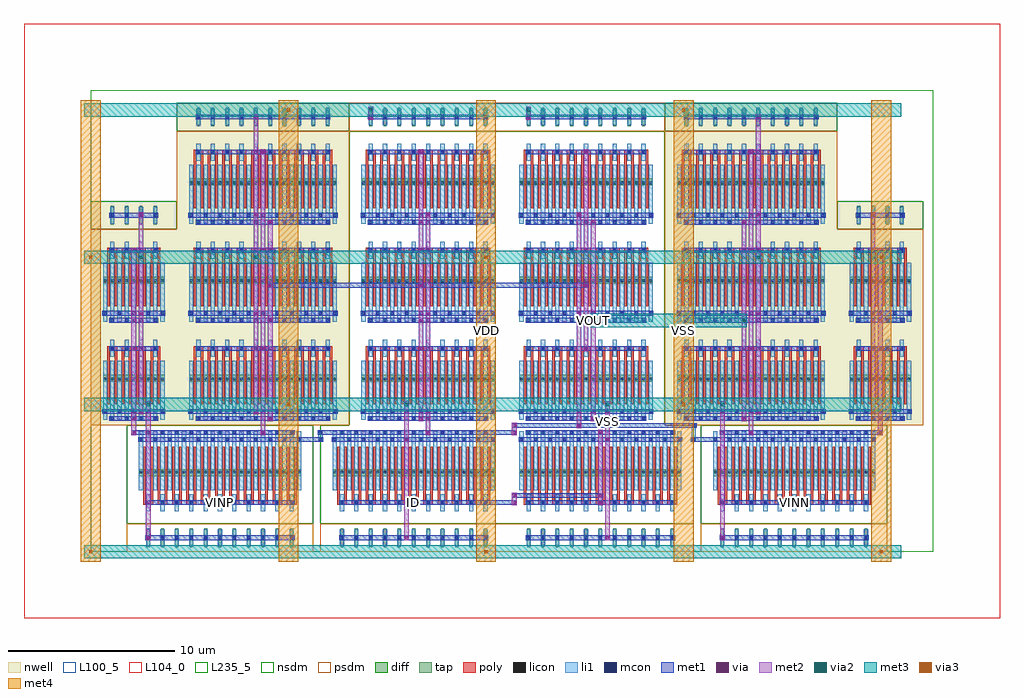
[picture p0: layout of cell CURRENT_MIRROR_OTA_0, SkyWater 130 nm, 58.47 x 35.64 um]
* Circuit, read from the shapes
.subckt CURRENT_MIRROR_OTA_0 ID VDD VINN VINP VOUT VSS
XM1 n1 VINP n2 VSS sky130_fd_pr__nfet_01v8 w=0.42 l=0.15 m=22
XM2 n2 ID VSS VSS sky130_fd_pr__nfet_01v8 w=0.42 l=0.15 m=22
XM3 n3 n3 n2 VSS sky130_fd_pr__nfet_01v8 w=0.42 l=0.15 m=54
XM4 ID ID VSS VSS sky130_fd_pr__nfet_01v8 w=0.42 l=0.15 m=22
XM5 VOUT n3 n2 VSS sky130_fd_pr__nfet_01v8 w=0.42 l=0.15 m=54
XM6 n4 VINN n2 VSS sky130_fd_pr__nfet_01v8 w=0.42 l=0.15 m=22
XM7 n1 n1 VDD VDD sky130_fd_pr__pfet_01v8 w=0.42 l=0.15 m=16
XM8 n3 n1 VDD VDD sky130_fd_pr__pfet_01v8 w=0.42 l=0.15 m=60
XM9 VOUT n4 VDD VDD sky130_fd_pr__pfet_01v8 w=0.42 l=0.15 m=60
XM10 n4 n4 VDD VDD sky130_fd_pr__pfet_01v8 w=0.42 l=0.15 m=16
.ends

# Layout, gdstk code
from math import pi, radians
import gdstk
lib = gdstk.Library(unit=1e-6, precision=1e-09)
def R(c, l, rs):  # rectangles x0, y0, x1, y1
    for r in rs: c.add(gdstk.rectangle(r[:2], r[2:], *l))
def A(c, l, x, y, w, h, nx, ny, dx, dy):  # array of equal rectangles
    R(c, l, [(x+i*dx, y+j*dy, x+i*dx+w, y+j*dy+h) for i in range(nx) for j in range(ny)])
def P(c, l, *ps):  # polygons
    for p in ps: c.add(gdstk.Polygon(p, *l))
nwell = (64, 20)
diff = (65, 20)
tap = (65, 44)
poly = (66, 20)
licon = (66, 44)
li1 = (67, 20)
mcon = (67, 44)
met1 = (68, 20)
via = (68, 44)
met2 = (69, 20)
via2 = (69, 44)
met3 = (70, 20)
via3 = (70, 44)
met4 = (71, 20)
nsdm = (93, 44)
psdm = (94, 20)
L100_5 = (100, 5)
L104_0 = (104, 0)
L235_5 = (235, 5)

dcl_nmos_s_92344100_x11_ = lib.new_cell('DCL_NMOS_S_92344100_X11_Y1_1725293918')
R(dcl_nmos_s_92344100_x11_, diff, [(0.735,2.625,10.445,3.045)])
A(dcl_nmos_s_92344100_x11_, tap, 1.205, 6.16, 0.17, 1.12, 11, 1, 0.86, 0)
A(dcl_nmos_s_92344100_x11_, poly, 1, 1.26, 0.15, 3.36, 22, 1, 0.43, 0)
A(dcl_nmos_s_92344100_x11_, poly, 1, 4.485, 0.58, 0.27, 11, 1, 0.86, 0)
A(dcl_nmos_s_92344100_x11_, licon, 0.775, 2.705, 0.17, 0.17, 3, 1, 0.43, 0)
A(dcl_nmos_s_92344100_x11_, licon, 1.635, 2.705, 0.17, 0.17, 3, 1, 0.43, 0)
A(dcl_nmos_s_92344100_x11_, licon, 2.495, 2.705, 0.17, 0.17, 3, 1, 0.43, 0)
A(dcl_nmos_s_92344100_x11_, licon, 3.355, 2.705, 0.17, 0.17, 3, 1, 0.43, 0)
A(dcl_nmos_s_92344100_x11_, licon, 4.215, 2.705, 0.17, 0.17, 3, 1, 0.43, 0)
A(dcl_nmos_s_92344100_x11_, licon, 5.075, 2.705, 0.17, 0.17, 3, 1, 0.43, 0)
A(dcl_nmos_s_92344100_x11_, licon, 5.935, 2.705, 0.17, 0.17, 3, 1, 0.43, 0)
A(dcl_nmos_s_92344100_x11_, licon, 6.795, 2.705, 0.17, 0.17, 3, 1, 0.43, 0)
A(dcl_nmos_s_92344100_x11_, licon, 7.655, 2.705, 0.17, 0.17, 3, 1, 0.43, 0)
A(dcl_nmos_s_92344100_x11_, licon, 8.515, 2.705, 0.17, 0.17, 3, 1, 0.43, 0)
A(dcl_nmos_s_92344100_x11_, licon, 9.375, 2.705, 0.17, 0.17, 3, 1, 0.43, 0)
A(dcl_nmos_s_92344100_x11_, licon, 1.205, 4.535, 0.17, 0.17, 11, 2, 0.86, 2.1)
A(dcl_nmos_s_92344100_x11_, li1, 0.735, 0.335, 0.25, 3.53, 23, 1, 0.43, 0)
A(dcl_nmos_s_92344100_x11_, li1, 1.165, 4.115, 0.25, 1.01, 11, 2, 0.86, 2.1)
A(dcl_nmos_s_92344100_x11_, mcon, 1.205, 0.335, 0.17, 0.17, 11, 2, 0.86, 4.2)
A(dcl_nmos_s_92344100_x11_, mcon, 0.775, 0.755, 0.17, 0.17, 12, 1, 0.86, 0)
A(dcl_nmos_s_92344100_x11_, mcon, 1.205, 6.635, 0.17, 0.17, 11, 1, 0.86, 0)
R(dcl_nmos_s_92344100_x11_, met1, [(1.12,0.28,10.06,0.56), (0.69,0.7,10.49,0.98), (1.12,4.48,10.06,4.76), (1.12,6.58,10.06,6.86)])
R(dcl_nmos_s_92344100_x11_, via, [(5.515,0.345,5.665,0.495), (5.945,0.765,6.095,0.915), (5.515,4.545,5.665,4.695), (5.945,6.645,6.095,6.795)])
R(dcl_nmos_s_92344100_x11_, met2, [(5.45,0.26,5.73,4.78), (5.88,0.68,6.16,6.88)])
R(dcl_nmos_s_92344100_x11_, nsdm, [(0,0,11.18,5.88)])
R(dcl_nmos_s_92344100_x11_, psdm, [(0,5.88,11.18,7.56)])
R(dcl_nmos_s_92344100_x11_, L100_5, [(0,0,11.18,7.56)])

dcl_pmos_s_60690635_x4_y = lib.new_cell('DCL_PMOS_S_60690635_X4_Y2_1725293919')
R(dcl_pmos_s_60690635_x4_y, nwell, [(0,0,5.16,13.44)])
R(dcl_pmos_s_60690635_x4_y, diff, [(0.735,2.625,4.425,3.045), (0.735,8.505,4.425,8.925)])
A(dcl_pmos_s_60690635_x4_y, tap, 1.205, 12.04, 0.17, 1.12, 4, 1, 0.86, 0)
A(dcl_pmos_s_60690635_x4_y, poly, 1, 1.26, 0.15, 3.36, 8, 2, 0.43, 5.88)
A(dcl_pmos_s_60690635_x4_y, poly, 1, 4.485, 0.58, 0.27, 4, 2, 0.86, 5.88)
A(dcl_pmos_s_60690635_x4_y, licon, 0.775, 2.705, 0.17, 0.17, 3, 2, 0.43, 5.88)
A(dcl_pmos_s_60690635_x4_y, licon, 1.635, 2.705, 0.17, 0.17, 3, 2, 0.43, 5.88)
A(dcl_pmos_s_60690635_x4_y, licon, 2.495, 2.705, 0.17, 0.17, 3, 2, 0.43, 5.88)
A(dcl_pmos_s_60690635_x4_y, licon, 3.355, 2.705, 0.17, 0.17, 3, 2, 0.43, 5.88)
A(dcl_pmos_s_60690635_x4_y, licon, 1.205, 4.535, 0.17, 0.17, 4, 2, 0.86, 5.88)
R(dcl_pmos_s_60690635_x4_y, licon, [(1.205,12.515,1.375,12.685), (1.205,12.515,1.375,12.685), (2.065,12.515,2.235,12.685), (2.065,12.515,2.235,12.685), (2.925,12.515,3.095,12.685), (2.925,12.515,3.095,12.685), (3.785,12.515,3.955,12.685), (3.785,12.515,3.955,12.685)])
A(dcl_pmos_s_60690635_x4_y, li1, 0.735, 0.335, 0.25, 3.53, 9, 2, 0.43, 5.88)
A(dcl_pmos_s_60690635_x4_y, li1, 1.165, 4.115, 0.25, 1.01, 4, 2, 0.86, 5.88)
A(dcl_pmos_s_60690635_x4_y, li1, 1.165, 12.095, 0.25, 1.01, 4, 1, 0.86, 0)
A(dcl_pmos_s_60690635_x4_y, mcon, 1.205, 0.335, 0.17, 0.17, 4, 2, 0.86, 4.2)
A(dcl_pmos_s_60690635_x4_y, mcon, 0.775, 0.755, 0.17, 0.17, 5, 2, 0.86, 5.88)
A(dcl_pmos_s_60690635_x4_y, mcon, 1.205, 6.215, 0.17, 0.17, 4, 2, 0.86, 4.2)
A(dcl_pmos_s_60690635_x4_y, mcon, 1.205, 12.515, 0.17, 0.17, 4, 1, 0.86, 0)
R(dcl_pmos_s_60690635_x4_y, met1, [(1.12,0.28,4.04,0.56), (0.69,0.7,4.47,0.98), (1.12,4.48,4.04,4.76), (1.12,6.16,4.04,6.44), (0.69,6.58,4.47,6.86), (1.12,10.36,4.04,10.64), (1.12,12.46,4.04,12.74)])
A(dcl_pmos_s_60690635_x4_y, via, 2.935, 0.765, 0.15, 0.15, 1, 3, 0, 5.88)
R(dcl_pmos_s_60690635_x4_y, via, [(2.505,0.345,2.655,0.495), (2.505,4.545,2.655,4.695), (2.505,6.225,2.655,6.375), (2.505,10.425,2.655,10.575)])
R(dcl_pmos_s_60690635_x4_y, met2, [(2.44,0.26,2.72,10.66), (2.87,0.68,3.15,12.76)])
R(dcl_pmos_s_60690635_x4_y, nsdm, [(0,11.76,5.16,13.44)])
R(dcl_pmos_s_60690635_x4_y, psdm, [(0,0,5.16,11.76)])
R(dcl_pmos_s_60690635_x4_y, L100_5, [(0,0,5.16,13.44)])

nmos_s_41291443_x11_y1_1 = lib.new_cell('NMOS_S_41291443_X11_Y1_1725293922')
R(nmos_s_41291443_x11_y1_1, diff, [(0.735,2.625,10.445,3.045)])
A(nmos_s_41291443_x11_y1_1, tap, 1.205, 6.16, 0.17, 1.12, 11, 1, 0.86, 0)
A(nmos_s_41291443_x11_y1_1, poly, 1, 1.26, 0.15, 3.36, 22, 1, 0.43, 0)
A(nmos_s_41291443_x11_y1_1, poly, 1, 4.485, 0.58, 0.27, 11, 1, 0.86, 0)
A(nmos_s_41291443_x11_y1_1, licon, 0.775, 2.705, 0.17, 0.17, 3, 1, 0.43, 0)
A(nmos_s_41291443_x11_y1_1, licon, 1.635, 2.705, 0.17, 0.17, 3, 1, 0.43, 0)
A(nmos_s_41291443_x11_y1_1, licon, 2.495, 2.705, 0.17, 0.17, 3, 1, 0.43, 0)
A(nmos_s_41291443_x11_y1_1, licon, 3.355, 2.705, 0.17, 0.17, 3, 1, 0.43, 0)
A(nmos_s_41291443_x11_y1_1, licon, 4.215, 2.705, 0.17, 0.17, 3, 1, 0.43, 0)
A(nmos_s_41291443_x11_y1_1, licon, 5.075, 2.705, 0.17, 0.17, 3, 1, 0.43, 0)
A(nmos_s_41291443_x11_y1_1, licon, 5.935, 2.705, 0.17, 0.17, 3, 1, 0.43, 0)
A(nmos_s_41291443_x11_y1_1, licon, 6.795, 2.705, 0.17, 0.17, 3, 1, 0.43, 0)
A(nmos_s_41291443_x11_y1_1, licon, 7.655, 2.705, 0.17, 0.17, 3, 1, 0.43, 0)
A(nmos_s_41291443_x11_y1_1, licon, 8.515, 2.705, 0.17, 0.17, 3, 1, 0.43, 0)
A(nmos_s_41291443_x11_y1_1, licon, 9.375, 2.705, 0.17, 0.17, 3, 1, 0.43, 0)
A(nmos_s_41291443_x11_y1_1, licon, 1.205, 4.535, 0.17, 0.17, 11, 2, 0.86, 2.1)
A(nmos_s_41291443_x11_y1_1, li1, 0.735, 0.335, 0.25, 3.53, 23, 1, 0.43, 0)
A(nmos_s_41291443_x11_y1_1, li1, 1.165, 4.115, 0.25, 1.01, 11, 2, 0.86, 2.1)
A(nmos_s_41291443_x11_y1_1, mcon, 1.205, 0.335, 0.17, 0.17, 11, 2, 0.86, 4.2)
A(nmos_s_41291443_x11_y1_1, mcon, 0.775, 0.755, 0.17, 0.17, 12, 1, 0.86, 0)
A(nmos_s_41291443_x11_y1_1, mcon, 1.205, 6.635, 0.17, 0.17, 11, 1, 0.86, 0)
R(nmos_s_41291443_x11_y1_1, met1, [(1.12,0.28,10.06,0.56), (0.69,0.7,10.49,0.98), (1.12,4.48,10.06,4.76), (1.12,6.58,10.06,6.86)])
R(nmos_s_41291443_x11_y1_1, via, [(5.945,0.765,6.095,0.915), (5.945,6.645,6.095,6.795)])
R(nmos_s_41291443_x11_y1_1, met2, [(5.88,0.68,6.16,6.88)])
R(nmos_s_41291443_x11_y1_1, nsdm, [(0,0,11.18,5.88)])
R(nmos_s_41291443_x11_y1_1, psdm, [(0,5.88,11.18,7.56)])
R(nmos_s_41291443_x11_y1_1, L100_5, [(0,0,11.18,7.56)])

pmos_s_33763385_x10_y3_1 = lib.new_cell('PMOS_S_33763385_X10_Y3_1725293923')
R(pmos_s_33763385_x10_y3_1, nwell, [(0,0,10.32,19.32)])
A(pmos_s_33763385_x10_y3_1, diff, 0.735, 2.625, 8.85, 0.42, 1, 3, 0, 5.88)
A(pmos_s_33763385_x10_y3_1, tap, 1.205, 17.92, 0.17, 1.12, 10, 1, 0.86, 0)
A(pmos_s_33763385_x10_y3_1, poly, 1, 1.26, 0.15, 3.36, 20, 3, 0.43, 5.88)
A(pmos_s_33763385_x10_y3_1, poly, 1, 4.485, 0.58, 0.27, 10, 3, 0.86, 5.88)
A(pmos_s_33763385_x10_y3_1, licon, 0.775, 2.705, 0.17, 0.17, 3, 3, 0.43, 5.88)
A(pmos_s_33763385_x10_y3_1, licon, 1.635, 2.705, 0.17, 0.17, 3, 3, 0.43, 5.88)
A(pmos_s_33763385_x10_y3_1, licon, 2.495, 2.705, 0.17, 0.17, 3, 3, 0.43, 5.88)
A(pmos_s_33763385_x10_y3_1, licon, 3.355, 2.705, 0.17, 0.17, 3, 3, 0.43, 5.88)
A(pmos_s_33763385_x10_y3_1, licon, 4.215, 2.705, 0.17, 0.17, 3, 3, 0.43, 5.88)
A(pmos_s_33763385_x10_y3_1, licon, 5.075, 2.705, 0.17, 0.17, 3, 3, 0.43, 5.88)
A(pmos_s_33763385_x10_y3_1, licon, 5.935, 2.705, 0.17, 0.17, 3, 3, 0.43, 5.88)
A(pmos_s_33763385_x10_y3_1, licon, 6.795, 2.705, 0.17, 0.17, 3, 3, 0.43, 5.88)
A(pmos_s_33763385_x10_y3_1, licon, 7.655, 2.705, 0.17, 0.17, 3, 3, 0.43, 5.88)
A(pmos_s_33763385_x10_y3_1, licon, 8.515, 2.705, 0.17, 0.17, 3, 3, 0.43, 5.88)
A(pmos_s_33763385_x10_y3_1, licon, 1.205, 4.535, 0.17, 0.17, 10, 3, 0.86, 5.88)
R(pmos_s_33763385_x10_y3_1, licon, [(1.205,18.395,1.375,18.565), (1.205,18.395,1.375,18.565), (1.205,18.395,1.375,18.565), (2.065,18.395,2.235,18.565), (2.065,18.395,2.235,18.565), (2.065,18.395,2.235,18.565), (2.925,18.395,3.095,18.565), (2.925,18.395,3.095,18.565), (2.925,18.395,3.095,18.565), (3.785,18.395,3.955,18.565), (3.785,18.395,3.955,18.565), (3.785,18.395,3.955,18.565), (4.645,18.395,4.815,18.565), (4.645,18.395,4.815,18.565), (4.645,18.395,4.815,18.565), (5.505,18.395,5.675,18.565), (5.505,18.395,5.675,18.565), (5.505,18.395,5.675,18.565), (6.365,18.395,6.535,18.565), (6.365,18.395,6.535,18.565), (6.365,18.395,6.535,18.565), (7.225,18.395,7.395,18.565), (7.225,18.395,7.395,18.565), (7.225,18.395,7.395,18.565), (8.085,18.395,8.255,18.565), (8.085,18.395,8.255,18.565), (8.085,18.395,8.255,18.565), (8.945,18.395,9.115,18.565), (8.945,18.395,9.115,18.565), (8.945,18.395,9.115,18.565)])
A(pmos_s_33763385_x10_y3_1, li1, 0.735, 0.335, 0.25, 3.53, 21, 3, 0.43, 5.88)
A(pmos_s_33763385_x10_y3_1, li1, 1.165, 4.115, 0.25, 1.01, 10, 3, 0.86, 5.88)
A(pmos_s_33763385_x10_y3_1, li1, 1.165, 17.975, 0.25, 1.01, 10, 1, 0.86, 0)
A(pmos_s_33763385_x10_y3_1, mcon, 1.205, 0.335, 0.17, 0.17, 10, 2, 0.86, 4.2)
A(pmos_s_33763385_x10_y3_1, mcon, 0.775, 0.755, 0.17, 0.17, 11, 3, 0.86, 5.88)
A(pmos_s_33763385_x10_y3_1, mcon, 1.205, 6.215, 0.17, 0.17, 10, 2, 0.86, 4.2)
A(pmos_s_33763385_x10_y3_1, mcon, 1.205, 12.095, 0.17, 0.17, 10, 2, 0.86, 4.2)
A(pmos_s_33763385_x10_y3_1, mcon, 1.205, 18.395, 0.17, 0.17, 10, 1, 0.86, 0)
A(pmos_s_33763385_x10_y3_1, met1, 0.69, 0.7, 8.94, 0.28, 1, 3, 0, 5.88)
R(pmos_s_33763385_x10_y3_1, met1, [(1.12,0.28,9.2,0.56), (1.12,4.48,9.2,4.76), (1.12,6.16,9.2,6.44), (1.12,10.36,9.2,10.64), (1.12,12.04,9.2,12.32), (1.12,16.24,9.2,16.52), (1.12,18.34,9.2,18.62)])
A(pmos_s_33763385_x10_y3_1, via, 4.655, 0.345, 0.15, 0.15, 1, 3, 0, 5.88)
A(pmos_s_33763385_x10_y3_1, via, 5.515, 0.765, 0.15, 0.15, 1, 4, 0, 5.88)
A(pmos_s_33763385_x10_y3_1, via, 5.085, 4.545, 0.15, 0.15, 1, 3, 0, 5.88)
R(pmos_s_33763385_x10_y3_1, met2, [(4.59,0.26,4.87,12.34), (5.45,0.68,5.73,18.64), (5.02,4.46,5.3,16.54)])
R(pmos_s_33763385_x10_y3_1, nsdm, [(0,17.64,10.32,19.32)])
R(pmos_s_33763385_x10_y3_1, psdm, [(0,0,10.32,17.64)])
R(pmos_s_33763385_x10_y3_1, L100_5, [(0,0,10.32,19.32)])

dcl_nmos_22653440_x9_y3_ = lib.new_cell('DCL_NMOS_22653440_X9_Y3_1725293917')
A(dcl_nmos_22653440_x9_y3_, diff, 0.735, 2.625, 7.99, 0.42, 1, 3, 0, 5.88)
A(dcl_nmos_22653440_x9_y3_, tap, 1.205, 17.92, 0.17, 1.12, 9, 1, 0.86, 0)
A(dcl_nmos_22653440_x9_y3_, poly, 1, 1.26, 0.15, 3.36, 18, 3, 0.43, 5.88)
A(dcl_nmos_22653440_x9_y3_, poly, 1, 4.485, 0.58, 0.27, 9, 3, 0.86, 5.88)
A(dcl_nmos_22653440_x9_y3_, licon, 0.775, 2.705, 0.17, 0.17, 3, 3, 0.43, 5.88)
A(dcl_nmos_22653440_x9_y3_, licon, 1.635, 2.705, 0.17, 0.17, 3, 3, 0.43, 5.88)
A(dcl_nmos_22653440_x9_y3_, licon, 2.495, 2.705, 0.17, 0.17, 3, 3, 0.43, 5.88)
A(dcl_nmos_22653440_x9_y3_, licon, 3.355, 2.705, 0.17, 0.17, 3, 3, 0.43, 5.88)
A(dcl_nmos_22653440_x9_y3_, licon, 4.215, 2.705, 0.17, 0.17, 3, 3, 0.43, 5.88)
A(dcl_nmos_22653440_x9_y3_, licon, 5.075, 2.705, 0.17, 0.17, 3, 3, 0.43, 5.88)
A(dcl_nmos_22653440_x9_y3_, licon, 5.935, 2.705, 0.17, 0.17, 3, 3, 0.43, 5.88)
A(dcl_nmos_22653440_x9_y3_, licon, 6.795, 2.705, 0.17, 0.17, 3, 3, 0.43, 5.88)
A(dcl_nmos_22653440_x9_y3_, licon, 7.655, 2.705, 0.17, 0.17, 3, 3, 0.43, 5.88)
A(dcl_nmos_22653440_x9_y3_, licon, 1.205, 4.535, 0.17, 0.17, 9, 3, 0.86, 5.88)
R(dcl_nmos_22653440_x9_y3_, licon, [(1.205,18.395,1.375,18.565), (1.205,18.395,1.375,18.565), (1.205,18.395,1.375,18.565), (2.065,18.395,2.235,18.565), (2.065,18.395,2.235,18.565), (2.065,18.395,2.235,18.565), (2.925,18.395,3.095,18.565), (2.925,18.395,3.095,18.565), (2.925,18.395,3.095,18.565), (3.785,18.395,3.955,18.565), (3.785,18.395,3.955,18.565), (3.785,18.395,3.955,18.565), (4.645,18.395,4.815,18.565), (4.645,18.395,4.815,18.565), (4.645,18.395,4.815,18.565), (5.505,18.395,5.675,18.565), (5.505,18.395,5.675,18.565), (5.505,18.395,5.675,18.565), (6.365,18.395,6.535,18.565), (6.365,18.395,6.535,18.565), (6.365,18.395,6.535,18.565), (7.225,18.395,7.395,18.565), (7.225,18.395,7.395,18.565), (7.225,18.395,7.395,18.565), (8.085,18.395,8.255,18.565), (8.085,18.395,8.255,18.565), (8.085,18.395,8.255,18.565)])
A(dcl_nmos_22653440_x9_y3_, li1, 0.735, 0.335, 0.25, 3.53, 19, 3, 0.43, 5.88)
A(dcl_nmos_22653440_x9_y3_, li1, 1.165, 4.115, 0.25, 1.01, 9, 3, 0.86, 5.88)
A(dcl_nmos_22653440_x9_y3_, li1, 1.165, 17.975, 0.25, 1.01, 9, 1, 0.86, 0)
A(dcl_nmos_22653440_x9_y3_, mcon, 1.205, 0.335, 0.17, 0.17, 9, 2, 0.86, 4.2)
A(dcl_nmos_22653440_x9_y3_, mcon, 0.775, 0.755, 0.17, 0.17, 10, 3, 0.86, 5.88)
A(dcl_nmos_22653440_x9_y3_, mcon, 1.205, 6.215, 0.17, 0.17, 9, 2, 0.86, 4.2)
A(dcl_nmos_22653440_x9_y3_, mcon, 1.205, 12.095, 0.17, 0.17, 9, 2, 0.86, 4.2)
A(dcl_nmos_22653440_x9_y3_, mcon, 1.205, 18.395, 0.17, 0.17, 9, 1, 0.86, 0)
A(dcl_nmos_22653440_x9_y3_, met1, 0.69, 0.7, 8.08, 0.28, 1, 3, 0, 5.88)
R(dcl_nmos_22653440_x9_y3_, met1, [(1.12,0.28,8.34,0.56), (1.12,4.48,8.34,4.76), (1.12,6.16,8.34,6.44), (1.12,10.36,8.34,10.64), (1.12,12.04,8.34,12.32), (1.12,16.24,8.34,16.52), (1.12,18.34,8.34,18.62)])
A(dcl_nmos_22653440_x9_y3_, via, 4.655, 0.765, 0.15, 0.15, 1, 3, 0, 5.88)
R(dcl_nmos_22653440_x9_y3_, via, [(4.225,0.345,4.375,0.495), (4.225,4.545,4.375,4.695), (4.225,6.225,4.375,6.375), (4.225,10.425,4.375,10.575), (4.225,12.105,4.375,12.255), (4.225,16.305,4.375,16.455)])
R(dcl_nmos_22653440_x9_y3_, met2, [(4.16,0.26,4.44,16.54), (4.59,0.68,4.87,12.76)])
R(dcl_nmos_22653440_x9_y3_, nsdm, [(0,0,9.46,17.64)])
R(dcl_nmos_22653440_x9_y3_, psdm, [(0,17.64,9.46,19.32)])
R(dcl_nmos_22653440_x9_y3_, L100_5, [(0,0,9.46,19.32)])

nmos_4t_75303516_x11_y1_ = lib.new_cell('NMOS_4T_75303516_X11_Y1_1725293921')
R(nmos_4t_75303516_x11_y1_, diff, [(0.735,2.625,10.445,3.045)])
A(nmos_4t_75303516_x11_y1_, tap, 1.205, 6.16, 0.17, 1.12, 11, 1, 0.86, 0)
A(nmos_4t_75303516_x11_y1_, poly, 1, 1.26, 0.15, 3.36, 22, 1, 0.43, 0)
A(nmos_4t_75303516_x11_y1_, poly, 1, 4.485, 0.58, 0.27, 11, 1, 0.86, 0)
A(nmos_4t_75303516_x11_y1_, licon, 0.775, 2.705, 0.17, 0.17, 3, 1, 0.43, 0)
A(nmos_4t_75303516_x11_y1_, licon, 1.635, 2.705, 0.17, 0.17, 3, 1, 0.43, 0)
A(nmos_4t_75303516_x11_y1_, licon, 2.495, 2.705, 0.17, 0.17, 3, 1, 0.43, 0)
A(nmos_4t_75303516_x11_y1_, licon, 3.355, 2.705, 0.17, 0.17, 3, 1, 0.43, 0)
A(nmos_4t_75303516_x11_y1_, licon, 4.215, 2.705, 0.17, 0.17, 3, 1, 0.43, 0)
A(nmos_4t_75303516_x11_y1_, licon, 5.075, 2.705, 0.17, 0.17, 3, 1, 0.43, 0)
A(nmos_4t_75303516_x11_y1_, licon, 5.935, 2.705, 0.17, 0.17, 3, 1, 0.43, 0)
A(nmos_4t_75303516_x11_y1_, licon, 6.795, 2.705, 0.17, 0.17, 3, 1, 0.43, 0)
A(nmos_4t_75303516_x11_y1_, licon, 7.655, 2.705, 0.17, 0.17, 3, 1, 0.43, 0)
A(nmos_4t_75303516_x11_y1_, licon, 8.515, 2.705, 0.17, 0.17, 3, 1, 0.43, 0)
A(nmos_4t_75303516_x11_y1_, licon, 9.375, 2.705, 0.17, 0.17, 3, 1, 0.43, 0)
A(nmos_4t_75303516_x11_y1_, licon, 1.205, 4.535, 0.17, 0.17, 11, 2, 0.86, 2.1)
A(nmos_4t_75303516_x11_y1_, li1, 0.735, 0.335, 0.25, 3.53, 23, 1, 0.43, 0)
A(nmos_4t_75303516_x11_y1_, li1, 1.165, 4.115, 0.25, 1.01, 11, 2, 0.86, 2.1)
A(nmos_4t_75303516_x11_y1_, mcon, 1.205, 0.335, 0.17, 0.17, 11, 2, 0.86, 4.2)
A(nmos_4t_75303516_x11_y1_, mcon, 0.775, 0.755, 0.17, 0.17, 12, 1, 0.86, 0)
A(nmos_4t_75303516_x11_y1_, mcon, 1.205, 6.635, 0.17, 0.17, 11, 1, 0.86, 0)
R(nmos_4t_75303516_x11_y1_, met1, [(1.12,0.28,10.06,0.56), (0.69,0.7,10.49,0.98), (1.12,4.48,10.06,4.76), (1.12,6.58,10.06,6.86)])
R(nmos_4t_75303516_x11_y1_, nsdm, [(0,0,11.18,5.88)])
R(nmos_4t_75303516_x11_y1_, psdm, [(0,5.88,11.18,7.56)])
R(nmos_4t_75303516_x11_y1_, L100_5, [(0,0,11.18,7.56)])

nmos_4t_60843501_x9_y3_1 = lib.new_cell('NMOS_4T_60843501_X9_Y3_1725293920')
A(nmos_4t_60843501_x9_y3_1, diff, 0.735, 2.625, 7.99, 0.42, 1, 3, 0, 5.88)
A(nmos_4t_60843501_x9_y3_1, tap, 1.205, 17.92, 0.17, 1.12, 9, 1, 0.86, 0)
A(nmos_4t_60843501_x9_y3_1, poly, 1, 1.26, 0.15, 3.36, 18, 3, 0.43, 5.88)
A(nmos_4t_60843501_x9_y3_1, poly, 1, 4.485, 0.58, 0.27, 9, 3, 0.86, 5.88)
A(nmos_4t_60843501_x9_y3_1, licon, 0.775, 2.705, 0.17, 0.17, 3, 3, 0.43, 5.88)
A(nmos_4t_60843501_x9_y3_1, licon, 1.635, 2.705, 0.17, 0.17, 3, 3, 0.43, 5.88)
A(nmos_4t_60843501_x9_y3_1, licon, 2.495, 2.705, 0.17, 0.17, 3, 3, 0.43, 5.88)
A(nmos_4t_60843501_x9_y3_1, licon, 3.355, 2.705, 0.17, 0.17, 3, 3, 0.43, 5.88)
A(nmos_4t_60843501_x9_y3_1, licon, 4.215, 2.705, 0.17, 0.17, 3, 3, 0.43, 5.88)
A(nmos_4t_60843501_x9_y3_1, licon, 5.075, 2.705, 0.17, 0.17, 3, 3, 0.43, 5.88)
A(nmos_4t_60843501_x9_y3_1, licon, 5.935, 2.705, 0.17, 0.17, 3, 3, 0.43, 5.88)
A(nmos_4t_60843501_x9_y3_1, licon, 6.795, 2.705, 0.17, 0.17, 3, 3, 0.43, 5.88)
A(nmos_4t_60843501_x9_y3_1, licon, 7.655, 2.705, 0.17, 0.17, 3, 3, 0.43, 5.88)
A(nmos_4t_60843501_x9_y3_1, licon, 1.205, 4.535, 0.17, 0.17, 9, 3, 0.86, 5.88)
R(nmos_4t_60843501_x9_y3_1, licon, [(1.205,18.395,1.375,18.565), (1.205,18.395,1.375,18.565), (1.205,18.395,1.375,18.565), (2.065,18.395,2.235,18.565), (2.065,18.395,2.235,18.565), (2.065,18.395,2.235,18.565), (2.925,18.395,3.095,18.565), (2.925,18.395,3.095,18.565), (2.925,18.395,3.095,18.565), (3.785,18.395,3.955,18.565), (3.785,18.395,3.955,18.565), (3.785,18.395,3.955,18.565), (4.645,18.395,4.815,18.565), (4.645,18.395,4.815,18.565), (4.645,18.395,4.815,18.565), (5.505,18.395,5.675,18.565), (5.505,18.395,5.675,18.565), (5.505,18.395,5.675,18.565), (6.365,18.395,6.535,18.565), (6.365,18.395,6.535,18.565), (6.365,18.395,6.535,18.565), (7.225,18.395,7.395,18.565), (7.225,18.395,7.395,18.565), (7.225,18.395,7.395,18.565), (8.085,18.395,8.255,18.565), (8.085,18.395,8.255,18.565), (8.085,18.395,8.255,18.565)])
A(nmos_4t_60843501_x9_y3_1, li1, 0.735, 0.335, 0.25, 3.53, 19, 3, 0.43, 5.88)
A(nmos_4t_60843501_x9_y3_1, li1, 1.165, 4.115, 0.25, 1.01, 9, 3, 0.86, 5.88)
A(nmos_4t_60843501_x9_y3_1, li1, 1.165, 17.975, 0.25, 1.01, 9, 1, 0.86, 0)
A(nmos_4t_60843501_x9_y3_1, mcon, 1.205, 0.335, 0.17, 0.17, 9, 2, 0.86, 4.2)
A(nmos_4t_60843501_x9_y3_1, mcon, 0.775, 0.755, 0.17, 0.17, 10, 3, 0.86, 5.88)
A(nmos_4t_60843501_x9_y3_1, mcon, 1.205, 6.215, 0.17, 0.17, 9, 2, 0.86, 4.2)
A(nmos_4t_60843501_x9_y3_1, mcon, 1.205, 12.095, 0.17, 0.17, 9, 2, 0.86, 4.2)
A(nmos_4t_60843501_x9_y3_1, mcon, 1.205, 18.395, 0.17, 0.17, 9, 1, 0.86, 0)
A(nmos_4t_60843501_x9_y3_1, met1, 0.69, 0.7, 8.08, 0.28, 1, 3, 0, 5.88)
R(nmos_4t_60843501_x9_y3_1, met1, [(1.12,0.28,8.34,0.56), (1.12,4.48,8.34,4.76), (1.12,6.16,8.34,6.44), (1.12,10.36,8.34,10.64), (1.12,12.04,8.34,12.32), (1.12,16.24,8.34,16.52), (1.12,18.34,8.34,18.62)])
A(nmos_4t_60843501_x9_y3_1, via, 4.225, 0.345, 0.15, 0.15, 1, 3, 0, 5.88)
A(nmos_4t_60843501_x9_y3_1, via, 5.085, 0.765, 0.15, 0.15, 1, 3, 0, 5.88)
A(nmos_4t_60843501_x9_y3_1, via, 4.655, 4.545, 0.15, 0.15, 1, 3, 0, 5.88)
R(nmos_4t_60843501_x9_y3_1, met2, [(4.16,0.26,4.44,12.34), (5.02,0.68,5.3,12.76), (4.59,4.46,4.87,16.54)])
R(nmos_4t_60843501_x9_y3_1, nsdm, [(0,0,9.46,17.64)])
R(nmos_4t_60843501_x9_y3_1, psdm, [(0,17.64,9.46,19.32)])
R(nmos_4t_60843501_x9_y3_1, L100_5, [(0,0,9.46,19.32)])

current_mirror_ota_0 = lib.new_cell('CURRENT_MIRROR_OTA_0')
R(current_mirror_ota_0, li1, [(13.635,6.635,13.885,6.805), (13.635,6.635,13.885,6.805), (13.635,6.635,13.885,6.805), (13.635,6.635,13.885,6.805), (13.635,6.635,13.885,6.805), (13.635,6.635,13.885,6.805), (13.635,6.635,13.885,6.805), (13.635,6.635,13.885,6.805), (35.995,6.635,36.245,6.805), (35.995,6.635,36.245,6.805), (13.635,6.72,13.885,7.14), (35.995,6.72,36.245,7.56), (13.635,7.055,13.885,7.225), (13.635,7.055,13.885,7.225), (13.635,7.055,13.885,7.225), (13.635,7.055,13.885,7.225), (13.635,7.055,13.885,7.225), (13.635,7.055,13.885,7.225), (13.635,7.055,13.885,7.225), (13.635,7.055,13.885,7.225), (35.995,7.475,36.245,7.645), (35.995,7.475,36.245,7.645)])
R(current_mirror_ota_0, mcon, [(13.675,6.635,13.845,6.805), (13.675,6.635,13.845,6.805), (13.675,6.635,13.845,6.805), (13.675,6.635,13.845,6.805), (13.675,6.635,13.845,6.805), (13.675,6.635,13.845,6.805), (13.675,6.635,13.845,6.805), (13.675,6.635,13.845,6.805), (36.035,6.635,36.205,6.805), (36.035,6.635,36.205,6.805), (13.675,7.055,13.845,7.225), (13.675,7.055,13.845,7.225), (13.675,7.055,13.845,7.225), (13.675,7.055,13.845,7.225), (13.675,7.055,13.845,7.225), (13.675,7.055,13.845,7.225), (13.675,7.055,13.845,7.225), (13.675,7.055,13.845,7.225), (36.035,7.475,36.205,7.645), (36.035,7.475,36.205,7.645)])
R(current_mirror_ota_0, met1, [(3.28,0.7,3.6,0.98), (3.28,0.7,3.6,0.98), (3.28,0.7,3.6,0.98), (37.68,0.7,38,0.98), (37.68,0.7,38,0.98), (37.68,0.7,38,0.98), (37.68,0.7,38,0.98), (23.65,2.8,25.37,3.08), (25.21,2.8,25.53,3.08), (25.21,2.8,25.53,3.08), (25.21,3.22,25.53,3.5), (25.21,3.22,25.53,3.5), (25.37,3.22,30.53,3.5), (30.37,3.22,30.69,3.5), (30.37,3.22,30.69,3.5), (12.47,6.58,13.76,6.86), (13.59,6.58,13.93,6.86), (13.59,6.58,13.93,6.86), (13.59,6.58,13.93,6.86), (13.59,6.58,13.93,6.86), (13.59,6.58,13.93,6.86), (13.59,6.58,13.93,6.86), (13.59,6.58,13.93,6.86), (13.59,6.58,13.93,6.86), (35.95,6.58,36.29,6.86), (35.95,6.58,36.29,6.86), (36.12,6.58,37.41,6.86), (2.42,7,2.74,7.28), (2.42,7,2.74,7.28), (2.42,7,2.74,7.28), (2.42,7,2.74,7.28), (2.58,7,3.44,7.28), (10.16,7,10.48,7.28), (10.16,7,10.48,7.28), (13.59,7,13.93,7.28), (13.59,7,13.93,7.28), (13.59,7,13.93,7.28), (13.59,7,13.93,7.28), (13.59,7,13.93,7.28), (13.59,7,13.93,7.28), (13.59,7,13.93,7.28), (13.59,7,13.93,7.28), (13.76,7,15.05,7.28), (20.05,7,20.37,7.28), (20.05,7,20.37,7.28), (20.05,7,20.37,7.28), (20.05,7,20.37,7.28), (20.05,7,20.37,7.28), (20.05,7,20.37,7.28), (23.65,7,25.37,7.28), (25.21,7,25.53,7.28), (25.21,7,25.53,7.28), (25.21,7,25.53,7.28), (25.21,7,25.53,7.28), (39.4,7,39.72,7.28), (39.4,7,39.72,7.28), (46.44,7,47.3,7.28), (47.14,7,47.46,7.28), (47.14,7,47.46,7.28), (47.14,7,47.46,7.28), (47.14,7,47.46,7.28), (25.21,7.42,25.53,7.7), (25.21,7.42,25.53,7.7), (25.21,7.42,25.53,7.7), (25.21,7.42,25.53,7.7), (25.37,7.42,29.24,7.7), (29.08,7.42,29.4,7.7), (29.08,7.42,29.4,7.7), (29.08,7.42,29.4,7.7), (29.08,7.42,29.4,7.7), (29.24,7.42,36.12,7.7), (35.95,7.42,36.29,7.7), (35.95,7.42,36.29,7.7), (10.59,15.82,10.91,16.1), (10.59,15.82,10.91,16.1), (10.59,15.82,10.91,16.1), (10.59,15.82,10.91,16.1), (10.75,15.82,19.78,16.1), (19.62,15.82,19.94,16.1), (19.62,15.82,19.94,16.1), (19.62,15.82,19.94,16.1), (19.62,15.82,19.94,16.1), (19.78,15.82,29.67,16.1), (29.51,15.82,29.83,16.1), (29.51,15.82,29.83,16.1), (16.61,25.9,16.93,26.18), (16.61,25.9,16.93,26.18), (16.61,25.9,16.93,26.18), (16.61,25.9,16.93,26.18), (16.61,25.9,16.93,26.18), (26.07,25.9,26.39,26.18), (26.07,25.9,26.39,26.18)])
P(current_mirror_ota_0, met1, [(0,0),(0,0),(0,0),(0,0)],
  [(0,0),(0,0),(0,0),(0,0)],
  [(0,0),(0,0),(0,0),(0,0)],
  [(0,0),(0,0),(0,0),(0,0)],
  [(0,0),(0,0),(0,0),(0,0)],
  [(0,0),(0,0),(0,0),(0,0)],
  [(0,0),(0,0),(0,0),(0,0)],
  [(0,0),(0,0),(0,0),(0,0)],
  [(0,0),(0,0),(0,0),(0,0)],
  [(0,0),(0,0),(0,0),(0,0)],
  [(0,0),(0,0),(0,0),(0,0)],
  [(0,0),(0,0),(0,0),(0,0)],
  [(0,0),(0,0),(0,0),(0,0)],
  [(0,0),(0,0),(0,0),(0,0)],
  [(0,0),(0,0),(0,0),(0,0)])
R(current_mirror_ota_0, via, [(3.365,0.765,3.515,0.915), (3.365,0.765,3.515,0.915), (3.365,0.765,3.515,0.915), (37.765,0.765,37.915,0.915), (37.765,0.765,37.915,0.915), (37.765,0.765,37.915,0.915), (37.765,0.765,37.915,0.915), (25.295,2.865,25.445,3.015), (25.295,2.865,25.445,3.015), (25.295,3.285,25.445,3.435), (25.295,3.285,25.445,3.435), (30.455,3.285,30.605,3.435), (30.455,3.285,30.605,3.435), (2.505,7.065,2.655,7.215), (2.505,7.065,2.655,7.215), (2.505,7.065,2.655,7.215), (2.505,7.065,2.655,7.215), (10.245,7.065,10.395,7.215), (10.245,7.065,10.395,7.215), (20.135,7.065,20.285,7.215), (20.135,7.065,20.285,7.215), (20.135,7.065,20.285,7.215), (20.135,7.065,20.285,7.215), (20.135,7.065,20.285,7.215), (20.135,7.065,20.285,7.215), (25.295,7.065,25.445,7.215), (25.295,7.065,25.445,7.215), (25.295,7.065,25.445,7.215), (25.295,7.065,25.445,7.215), (39.485,7.065,39.635,7.215), (39.485,7.065,39.635,7.215), (47.225,7.065,47.375,7.215), (47.225,7.065,47.375,7.215), (47.225,7.065,47.375,7.215), (47.225,7.065,47.375,7.215), (25.295,7.485,25.445,7.635), (25.295,7.485,25.445,7.635), (25.295,7.485,25.445,7.635), (25.295,7.485,25.445,7.635), (29.165,7.485,29.315,7.635), (29.165,7.485,29.315,7.635), (29.165,7.485,29.315,7.635), (29.165,7.485,29.315,7.635), (10.675,15.885,10.825,16.035), (10.675,15.885,10.825,16.035), (10.675,15.885,10.825,16.035), (10.675,15.885,10.825,16.035), (19.705,15.885,19.855,16.035), (19.705,15.885,19.855,16.035), (19.705,15.885,19.855,16.035), (19.705,15.885,19.855,16.035), (29.595,15.885,29.745,16.035), (29.595,15.885,29.745,16.035), (16.695,25.965,16.845,26.115), (16.695,25.965,16.845,26.115), (16.695,25.965,16.845,26.115), (16.695,25.965,16.845,26.115), (16.695,25.965,16.845,26.115), (26.155,25.965,26.305,26.115), (26.155,25.965,26.305,26.115)])
R(current_mirror_ota_0, met2, [(3.3,0.68,3.58,1), (3.3,0.68,3.58,1), (3.3,0.68,3.58,1), (37.7,0.68,37.98,1), (37.7,0.68,37.98,1), (37.7,0.68,37.98,1), (37.7,0.68,37.98,1), (3.3,0.84,3.58,8.82), (37.7,0.84,37.98,8.82), (25.23,2.78,25.51,3.1), (25.23,2.78,25.51,3.1), (25.23,2.94,25.51,3.36), (25.23,3.2,25.51,3.52), (25.23,3.2,25.51,3.52), (30.39,3.2,30.67,3.52), (30.39,3.2,30.67,3.52), (18.78,6.72,19.06,8.82), (30.82,6.72,31.1,8.82), (2.44,6.98,2.72,7.3), (2.44,6.98,2.72,7.3), (2.44,6.98,2.72,7.3), (2.44,6.98,2.72,7.3), (10.18,6.98,10.46,7.3), (10.18,6.98,10.46,7.3), (20.07,6.98,20.35,7.3), (20.07,6.98,20.35,7.3), (20.07,6.98,20.35,7.3), (20.07,6.98,20.35,7.3), (20.07,6.98,20.35,7.3), (20.07,6.98,20.35,7.3), (25.23,6.98,25.51,7.3), (25.23,6.98,25.51,7.3), (25.23,6.98,25.51,7.3), (25.23,6.98,25.51,7.3), (39.42,6.98,39.7,7.3), (39.42,6.98,39.7,7.3), (47.16,6.98,47.44,7.3), (47.16,6.98,47.44,7.3), (47.16,6.98,47.44,7.3), (47.16,6.98,47.44,7.3), (2.44,7.14,2.72,7.98), (10.18,7.14,10.46,12.18), (20.07,7.14,20.35,8.4), (25.23,7.14,25.51,7.56), (39.42,7.14,39.7,12.18), (47.16,7.14,47.44,7.98), (25.23,7.4,25.51,7.72), (25.23,7.4,25.51,7.72), (25.23,7.4,25.51,7.72), (25.23,7.4,25.51,7.72), (29.1,7.4,29.38,7.72), (29.1,7.4,29.38,7.72), (29.1,7.4,29.38,7.72), (29.1,7.4,29.38,7.72), (29.1,7.56,29.38,8.4), (3.3,8.635,3.58,9.005), (3.3,8.635,3.58,9.005), (3.3,8.635,3.58,9.005), (18.78,8.635,19.06,9.005), (18.78,8.635,19.06,9.005), (18.78,8.635,19.06,9.005), (18.78,8.635,19.06,9.005), (18.78,8.635,19.06,9.005), (18.78,8.635,19.06,9.005), (30.82,8.635,31.1,9.005), (30.82,8.635,31.1,9.005), (30.82,8.635,31.1,9.005), (30.82,8.635,31.1,9.005), (30.82,8.635,31.1,9.005), (30.82,8.635,31.1,9.005), (30.82,8.635,31.1,9.005), (37.7,8.635,37.98,9.005), (37.7,8.635,37.98,9.005), (37.7,8.635,37.98,9.005), (37.7,8.635,37.98,9.005), (29.96,13.675,30.24,14.045), (29.96,13.675,30.24,14.045), (38.99,13.675,39.27,14.045), (38.99,13.675,39.27,14.045), (10.61,15.8,10.89,16.12), (10.61,15.8,10.89,16.12), (10.61,15.8,10.89,16.12), (10.61,15.8,10.89,16.12), (19.64,15.8,19.92,16.12), (19.64,15.8,19.92,16.12), (19.64,15.8,19.92,16.12), (19.64,15.8,19.92,16.12), (29.53,15.8,29.81,16.12), (29.53,15.8,29.81,16.12), (2.87,17.455,3.15,17.825), (2.87,17.455,3.15,17.825), (2.87,17.455,3.15,17.825), (2.87,17.455,3.15,17.825), (9.75,17.455,10.03,17.825), (9.75,17.455,10.03,17.825), (9.75,17.455,10.03,17.825), (39.85,17.455,40.13,17.825), (39.85,17.455,40.13,17.825), (46.73,17.455,47.01,17.825), (46.73,17.455,47.01,17.825), (46.73,17.455,47.01,17.825), (46.73,17.455,47.01,17.825), (46.73,17.455,47.01,17.825), (16.63,25.88,16.91,26.2), (16.63,25.88,16.91,26.2), (16.63,25.88,16.91,26.2), (16.63,25.88,16.91,26.2), (16.63,25.88,16.91,26.2), (26.09,25.88,26.37,26.2), (26.09,25.88,26.37,26.2), (16.63,26.04,16.91,26.46), (26.09,26.04,26.37,26.46), (16.63,26.275,16.91,26.645), (16.63,26.275,16.91,26.645), (16.63,26.275,16.91,26.645), (16.63,26.275,16.91,26.645), (16.63,26.275,16.91,26.645), (26.09,26.275,26.37,26.645), (26.09,26.275,26.37,26.645)])
P(current_mirror_ota_0, met2, [(0,0),(0,0),(0,0),(0,0)],
  [(0,0),(0,0),(0,0),(0,0)],
  [(0,0),(0,0),(0,0),(0,0)],
  [(0,0),(0,0),(0,0),(0,0)],
  [(0,0),(0,0),(0,0),(0,0)],
  [(0,0),(0,0),(0,0),(0,0)],
  [(0,0),(0,0),(0,0),(0,0)],
  [(0,0),(0,0),(0,0),(0,0)],
  [(0,0),(0,0),(0,0),(0,0)],
  [(0,0),(0,0),(0,0),(0,0)],
  [(0,0),(0,0),(0,0),(0,0)],
  [(0,0),(0,0),(0,0),(0,0)],
  [(0,0),(0,0),(0,0),(0,0)],
  [(0,0),(0,0),(0,0),(0,0)],
  [(0,0),(0,0),(0,0),(0,0)],
  [(0,0),(0,0),(0,0),(0,0)],
  [(0,0),(0,0),(0,0),(0,0)],
  [(0,0),(0,0),(0,0),(0,0)],
  [(0,0),(0,0),(0,0),(0,0)])
R(current_mirror_ota_0, via2, [(3.34,8.72,3.54,8.92), (3.34,8.72,3.54,8.92), (3.34,8.72,3.54,8.92), (18.82,8.72,19.02,8.92), (18.82,8.72,19.02,8.92), (18.82,8.72,19.02,8.92), (18.82,8.72,19.02,8.92), (18.82,8.72,19.02,8.92), (18.82,8.72,19.02,8.92), (30.86,8.72,31.06,8.92), (30.86,8.72,31.06,8.92), (30.86,8.72,31.06,8.92), (30.86,8.72,31.06,8.92), (30.86,8.72,31.06,8.92), (30.86,8.72,31.06,8.92), (30.86,8.72,31.06,8.92), (37.74,8.72,37.94,8.92), (37.74,8.72,37.94,8.92), (37.74,8.72,37.94,8.92), (37.74,8.72,37.94,8.92), (30,13.76,30.2,13.96), (30,13.76,30.2,13.96), (39.03,13.76,39.23,13.96), (39.03,13.76,39.23,13.96), (2.91,17.54,3.11,17.74), (2.91,17.54,3.11,17.74), (2.91,17.54,3.11,17.74), (2.91,17.54,3.11,17.74), (9.79,17.54,9.99,17.74), (9.79,17.54,9.99,17.74), (9.79,17.54,9.99,17.74), (39.89,17.54,40.09,17.74), (39.89,17.54,40.09,17.74), (46.77,17.54,46.97,17.74), (46.77,17.54,46.97,17.74), (46.77,17.54,46.97,17.74), (46.77,17.54,46.97,17.74), (46.77,17.54,46.97,17.74), (16.67,26.36,16.87,26.56), (16.67,26.36,16.87,26.56), (16.67,26.36,16.87,26.56), (16.67,26.36,16.87,26.56), (16.67,26.36,16.87,26.56), (26.13,26.36,26.33,26.56), (26.13,26.36,26.33,26.56)])
A(current_mirror_ota_0, met3, -0.4, -0.4, 4.24, 0.8, 3, 4, 3.44, 8.82)
A(current_mirror_ota_0, met3, -0.165, -0.4, 0.33, 0.8, 3, 1, 23.68, 0)
A(current_mirror_ota_0, met3, 9.92, -0.4, 2.32, 0.8, 1, 4, 0, 8.82)
A(current_mirror_ota_0, met3, 11.44, -0.4, 2.72, 0.8, 1, 4, 0, 8.82)
A(current_mirror_ota_0, met3, 13.36, -0.4, 4.24, 0.8, 1, 4, 0, 8.82)
A(current_mirror_ota_0, met3, 16.8, -0.4, 4.24, 0.8, 1, 4, 0, 8.82)
A(current_mirror_ota_0, met3, 20.24, -0.4, 3.84, 0.8, 1, 4, 0, 8.82)
A(current_mirror_ota_0, met3, 23.28, -0.4, 1.2, 0.8, 1, 4, 0, 8.82)
A(current_mirror_ota_0, met3, 23.68, -0.4, 4.24, 0.8, 3, 4, 3.44, 8.82)
A(current_mirror_ota_0, met3, 34, -0.4, 1.92, 0.8, 1, 4, 0, 8.82)
A(current_mirror_ota_0, met3, 35.12, -0.4, 3.12, 0.8, 1, 4, 0, 8.82)
A(current_mirror_ota_0, met3, 37.44, -0.4, 4.24, 0.8, 1, 4, 0, 8.82)
A(current_mirror_ota_0, met3, 40.88, -0.4, 4.24, 0.8, 1, 4, 0, 8.82)
A(current_mirror_ota_0, met3, 44.32, -0.4, 3.44, 0.8, 1, 4, 0, 8.82)
A(current_mirror_ota_0, met3, 46.96, -0.4, 1.6, 0.8, 1, 4, 0, 8.82)
R(current_mirror_ota_0, met3, [(3.275,8.42,3.605,9.22), (3.275,8.42,3.605,9.22), (3.275,8.42,3.605,9.22), (11.675,8.42,12.005,9.22), (18.755,8.42,19.085,9.22), (18.755,8.42,19.085,9.22), (18.755,8.42,19.085,9.22), (18.755,8.42,19.085,9.22), (18.755,8.42,19.085,9.22), (18.755,8.42,19.085,9.22), (30.795,8.42,31.125,9.22), (30.795,8.42,31.125,9.22), (30.795,8.42,31.125,9.22), (30.795,8.42,31.125,9.22), (30.795,8.42,31.125,9.22), (30.795,8.42,31.125,9.22), (30.795,8.42,31.125,9.22), (35.355,8.42,35.685,9.22), (37.675,8.42,38.005,9.22), (37.675,8.42,38.005,9.22), (37.675,8.42,38.005,9.22), (37.675,8.42,38.005,9.22), (29.935,13.46,30.265,14.26), (29.935,13.46,30.265,14.26), (30.1,13.46,39.13,14.26), (38.965,13.46,39.295,14.26), (38.965,13.46,39.295,14.26), (-0.165,17.24,0.165,18.04), (2.845,17.24,3.175,18.04), (2.845,17.24,3.175,18.04), (2.845,17.24,3.175,18.04), (2.845,17.24,3.175,18.04), (9.725,17.24,10.055,18.04), (9.725,17.24,10.055,18.04), (9.725,17.24,10.055,18.04), (23.515,17.24,23.845,18.04), (39.825,17.24,40.155,18.04), (39.825,17.24,40.155,18.04), (46.705,17.24,47.035,18.04), (46.705,17.24,47.035,18.04), (46.705,17.24,47.035,18.04), (46.705,17.24,47.035,18.04), (46.705,17.24,47.035,18.04), (47.195,17.24,47.525,18.04), (11.675,26.06,12.005,26.86), (16.605,26.06,16.935,26.86), (16.605,26.06,16.935,26.86), (16.605,26.06,16.935,26.86), (16.605,26.06,16.935,26.86), (16.605,26.06,16.935,26.86), (26.065,26.06,26.395,26.86), (26.065,26.06,26.395,26.86), (35.355,26.06,35.685,26.86)])
A(current_mirror_ota_0, via3, -0.1, -0.1, 0.2, 0.2, 3, 2, 23.68, 17.64)
R(current_mirror_ota_0, via3, [(11.74,8.72,11.94,8.92), (35.42,8.72,35.62,8.92), (11.74,26.36,11.94,26.56), (35.42,26.36,35.62,26.56)])
A(current_mirror_ota_0, met4, -0.59, -0.59, 1.18, 10, 5, 3, 11.84, 8.82)
A(current_mirror_ota_0, met4, -0.59, -0.165, 1.18, 0.33, 3, 2, 23.68, 17.64)
R(current_mirror_ota_0, met4, [(11.25,8.655,12.43,8.985), (34.93,8.655,36.11,8.985), (11.25,26.295,12.43,26.625), (34.93,26.295,36.11,26.625)])
R(current_mirror_ota_0, L104_0, [(-4,-4,54.47,31.64)])
R(current_mirror_ota_0, L235_5, [(0,0,50.47,27.64)])
current_mirror_ota_0.add(gdstk.Reference(dcl_nmos_s_92344100_x11_, (24.94,7.56), x_reflection=True))
current_mirror_ota_0.add(gdstk.Reference(dcl_pmos_s_60690635_x4_y, (49.88,7.56), rotation=pi, x_reflection=True))
current_mirror_ota_0.add(gdstk.Reference(dcl_pmos_s_60690635_x4_y, (0,7.56)))
current_mirror_ota_0.add(gdstk.Reference(nmos_s_41291443_x11_y1_1, (24.94,7.56), rotation=pi))
current_mirror_ota_0.add(gdstk.Reference(pmos_s_33763385_x10_y3_1, (15.48,7.56), rotation=pi, x_reflection=True))
current_mirror_ota_0.add(gdstk.Reference(pmos_s_33763385_x10_y3_1, (34.4,7.56)))
current_mirror_ota_0.add(gdstk.Reference(dcl_nmos_22653440_x9_y3_, (15.48,7.56)))
current_mirror_ota_0.add(gdstk.Reference(nmos_4t_75303516_x11_y1_, (47.73,7.56), rotation=pi))
current_mirror_ota_0.add(gdstk.Reference(nmos_4t_75303516_x11_y1_, (2.15,7.56), x_reflection=True))
current_mirror_ota_0.add(gdstk.Reference(nmos_4t_60843501_x9_y3_1, (34.4,7.56), rotation=pi, x_reflection=True))
current_mirror_ota_0.add(gdstk.Label('ID', (19.35,2.94), layer=68, texttype=5))
current_mirror_ota_0.add(gdstk.Label('VOUT', (30.1,13.86), layer=69, texttype=5))
current_mirror_ota_0.add(gdstk.Label('VINN', (42.14,2.94), layer=68, texttype=5))
current_mirror_ota_0.add(gdstk.Label('VINP', (7.74,2.94), layer=68, texttype=5))
current_mirror_ota_0.add(gdstk.Label('VSS', (30.96,7.77), layer=69, texttype=5))
current_mirror_ota_0.add(gdstk.Label('VSS', (35.52,13.23), layer=71, texttype=5))
current_mirror_ota_0.add(gdstk.Label('VSS', (35.52,13.23), layer=71, texttype=5))
current_mirror_ota_0.add(gdstk.Label('VSS', (35.52,13.23), layer=71, texttype=5))
current_mirror_ota_0.add(gdstk.Label('VSS', (35.52,13.23), layer=71, texttype=5))
current_mirror_ota_0.add(gdstk.Label('VSS', (35.52,13.23), layer=71, texttype=5))
current_mirror_ota_0.add(gdstk.Label('VSS', (35.52,13.23), layer=71, texttype=5))
current_mirror_ota_0.add(gdstk.Label('VSS', (35.52,13.23), layer=71, texttype=5))
current_mirror_ota_0.add(gdstk.Label('VSS', (35.52,13.23), layer=71, texttype=5))
current_mirror_ota_0.add(gdstk.Label('VSS', (35.52,13.23), layer=71, texttype=5))
current_mirror_ota_0.add(gdstk.Label('VSS', (35.52,13.23), layer=71, texttype=5))
current_mirror_ota_0.add(gdstk.Label('VSS', (35.52,13.23), layer=71, texttype=5))
current_mirror_ota_0.add(gdstk.Label('VSS', (35.52,13.23), layer=71, texttype=5))
current_mirror_ota_0.add(gdstk.Label('VSS', (35.52,13.23), layer=71, texttype=5))
current_mirror_ota_0.add(gdstk.Label('VSS', (35.52,13.23), layer=71, texttype=5))
current_mirror_ota_0.add(gdstk.Label('VSS', (35.52,13.23), layer=71, texttype=5))
current_mirror_ota_0.add(gdstk.Label('VSS', (35.52,13.23), layer=71, texttype=5))
current_mirror_ota_0.add(gdstk.Label('VDD', (23.68,13.23), layer=71, texttype=5))
current_mirror_ota_0.add(gdstk.Label('VDD', (23.68,13.23), layer=71, texttype=5))
current_mirror_ota_0.add(gdstk.Label('VDD', (23.68,13.23), layer=71, texttype=5))
current_mirror_ota_0.add(gdstk.Label('VDD', (23.68,13.23), layer=71, texttype=5))
current_mirror_ota_0.add(gdstk.Label('VDD', (23.68,13.23), layer=71, texttype=5))
current_mirror_ota_0.add(gdstk.Label('VDD', (23.68,13.23), layer=71, texttype=5))
current_mirror_ota_0.add(gdstk.Label('VDD', (23.68,13.23), layer=71, texttype=5))
current_mirror_ota_0.add(gdstk.Label('VDD', (23.68,13.23), layer=71, texttype=5))

lib.write_gds('CURRENT_MIRROR_OTA_0.gds')
